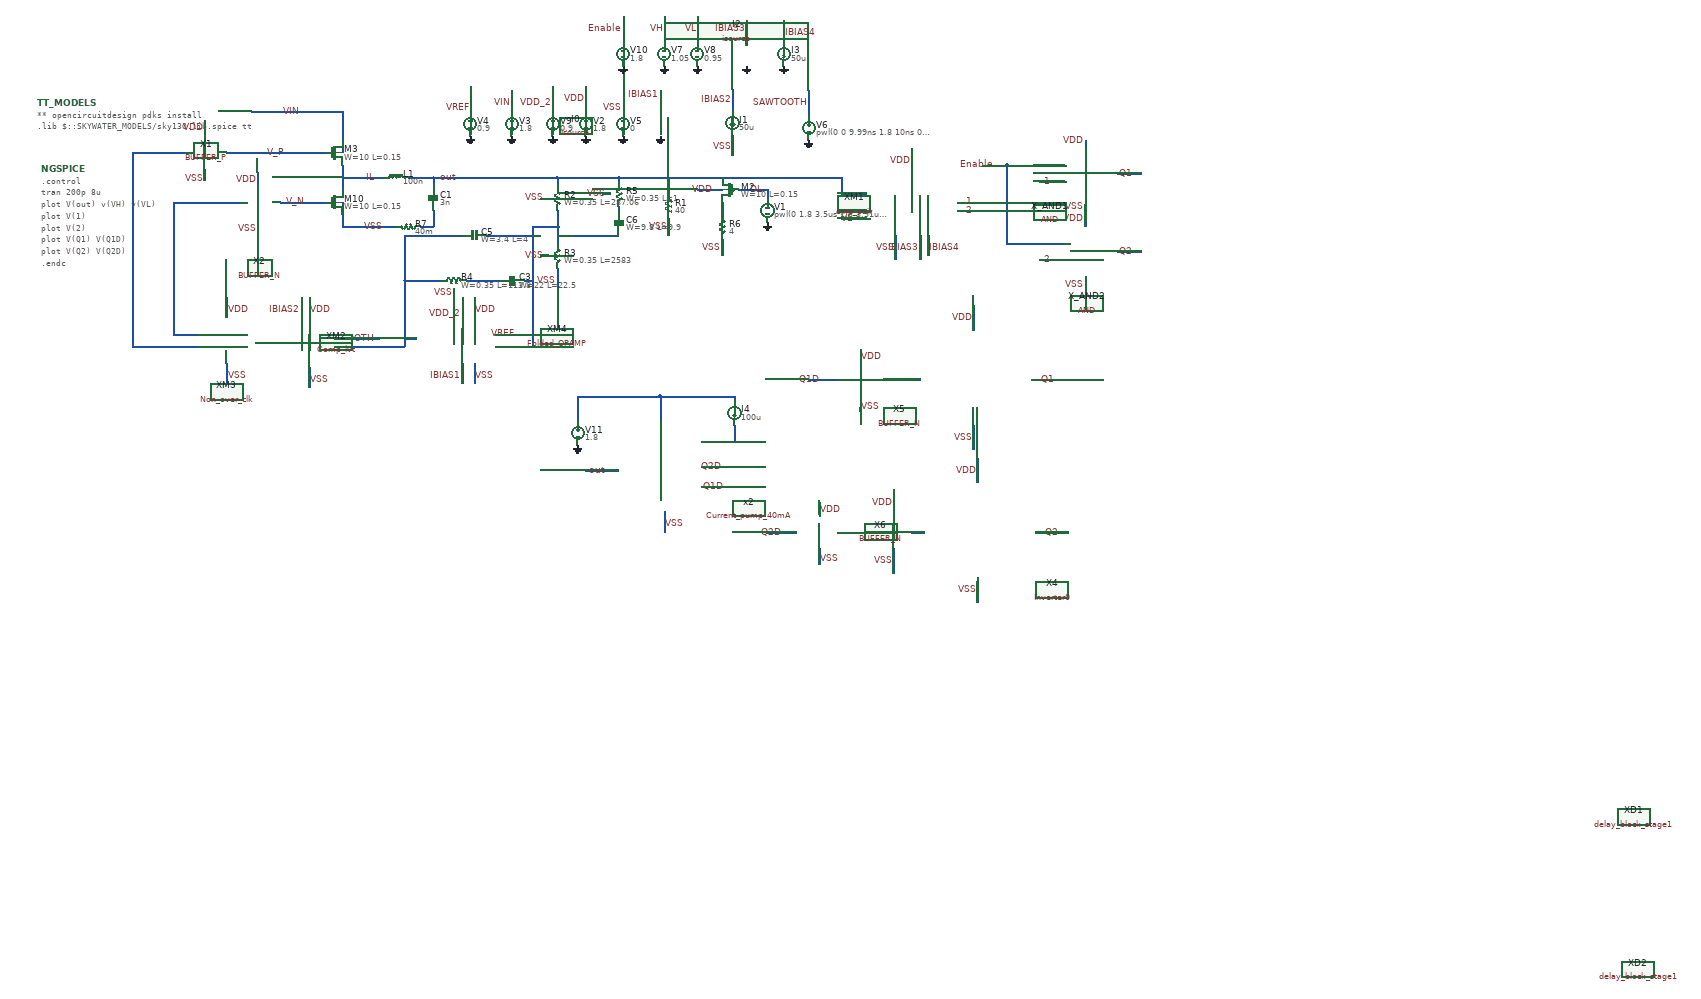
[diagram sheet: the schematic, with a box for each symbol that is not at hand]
v {xschem version=3.0.0 file_version=1.2 }
G {}
K {}
V {}
S {}
E {}
N 470 80 470 140 {
lab=IL}
N 470 20 470 50 {
lab=VIN}
N 380 50 430 50 {
lab=V_P}
N 470 -50 470 20 {
lab=VIN}
N 250 -50 470 -50 {
lab=VIN}
N 470 200 470 230 {
lab=VSS}
N 470 110 530 110 {
lab=IL}
N 530 110 570 110 {
lab=IL}
N 690 110 690 130 {
lab=out}
N 630 110 690 110 {
lab=out}
N 690 190 690 230 {
lab=#net1}
N 690 110 800 110 {
lab=out}
N 790 400 790 450 {
lab=VDD}
N 760 400 760 450 {
lab=VDD_2}
N 790 560 790 610 {
lab=VSS}
N 760 560 760 610 {
lab=IBIAS1}
N 840 520 890 520 {
lab=#net2}
N 840 490 890 490 {
lab=VREF}
N 880 -100 880 -50 {
lab=VIN}
N 980 -110 980 -50 {
lab=VDD_2}
N 1060 -60 1060 -50 {
lab=VDD}
N 1060 -110 1060 -60 {
lab=VDD}
N 1150 -80 1150 -60 {
lab=VSS}
N 1150 -60 1150 -50 {
lab=VSS}
N 1150 -110 1150 -80 {
lab=VSS}
N 1240 -100 1240 -40 {
lab=IBIAS1}
N 390 400 390 450 {
lab=VDD}
N 390 570 390 620 {
lab=VSS}
N 780 -80 780 -60 {
lab=VREF}
N 780 -60 780 -50 {
lab=VREF}
N 780 -110 780 -80 {
lab=VREF}
N 890 520 920 520 {
lab=#net2}
N 1415 7.5 1415 57.5 {
lab=VSS}
N 370 400 370 450 {
lab=IBIAS2}
N 1600 -100 1600 -40 {
lab=SAWTOOTH}
N 190 50 380 50 {
lab=V_P}
N 800 110 980 110 {
lab=out}
N 990 110 990 130 {
lab=out}
N 990 190 990 240 {
lab=#net2}
N 990 330 990 380 {
lab=VSS}
N 770 360 850 360 {
lab=#net3}
N 620 360 710 360 {
lab=#net4}
N 620 360 620 500 {
lab=#net4}
N 930 360 930 490 {
lab=#net2}
N 910 360 930 360 {
lab=#net2}
N 620 250 760 250 {
lab=#net4}
N 820 250 930 250 {
lab=#net2}
N 930 290 930 360 {
lab=#net2}
N 620 500 650 500 {
lab=#net4}
N 930 490 930 520 {
lab=#net2}
N 920 520 930 520 {
lab=#net2}
N 990 110 1140 110 {
lab=out}
N 1140 110 1140 120 {
lab=out}
N 1140 180 1140 190 {
lab=#net5}
N 980 110 990 110 {
lab=out}
N 930 230 930 290 {
lab=#net2}
N 930 230 990 230 {
lab=#net2}
N 990 240 990 270 {
lab=#net2}
N 1260 110 1260 150 {
lab=out}
N 1140 110 1260 110 {
lab=out}
N 1260 210 1260 250 {
lab=VSS}
N 450 520 620 520 {
lab=#net4}
N 620 500 620 520 {
lab=#net4}
N 380 170 430 170 {
lab=V_N}
N 470 170 470 200 {
lab=VSS}
N 1260 110 1390 110 {
lab=out}
N 1390 260 1390 300 {
lab=VSS}
N 1390 170 1390 200 {
lab=#net6}
N 1430 140 1500 140 {
lab=DL}
N 1500 140 1500 160 {
lab=DL}
N 190 400 190 450 {
lab=VDD}
N 190 560 190 610 {
lab=VSS}
N -40 50 90 50 {
lab=#net7}
N -40 50 -40 490 {
lab=#net7}
N 135 90 135 117.5 {
lab=VSS}
N 135 -27.5 135 7.5 {
lab=VDD}
N 320 170 380 170 {
lab=V_N}
N 60 170 220 170 {
lab=#net8}
N 60 170 60 260 {
lab=#net8}
N 265 210 265 247.5 {
lab=VSS}
N 265 97.5 265 127.5 {
lab=VDD}
N 60 490 120 490 {
lab=#net8}
N 60 260 60 490 {
lab=#net8}
N -40 520 120 520 {
lab=#net7}
N -40 490 -40 520 {
lab=#net7}
N 620 250 620 360 {
lab=#net4}
N 990 250 1040 250 {
lab=#net2}
N 1040 250 1140 250 {
lab=#net2}
N 790 560 790 610 {
lab=VSS}
N 1330 140 1390 140 {
lab=VDD}
N 1415 -102.5 1415 -52.5 {
lab=IBIAS2}
N 270 510 320 510 {
lab=#net9}
N 450 500 560 500 {
lab=SAWTOOTH}
N 740 380 740 400 {
lab=VSS}
N 1100 150 1120 150 {
lab=VSS}
N 950 160 970 160 {
lab=VSS}
N 950 300 970 300 {
lab=VSS}
N 470 230 600 230 {
lab=VSS}
N 660 230 690 230 {
lab=#net1}
N 260 510 270 510 {
lab=#net9}
N 1960 170 2010 170 {
lab=1}
N 1960 190 2010 190 {
lab=2}
N 1890 250 1890 300 {
lab=IBIAS4}
N 1870 250 1870 310 {
lab=IBIAS3}
N 1810 250 1810 310 {
lab=VSS}
N 1850 40 1850 100 {
lab=VDD}
N 1680 150 1740 150 {
lab=out}
N 1680 190 1740 190 {
lab=VH}
N 1680 210 1740 210 {
lab=VL}
N 1680 110 1680 150 {
lab=out}
N 1390 110 1680 110 {
lab=out}
N 1450 -270 1450 -210 {
lab=IBIAS3}
N 1540 -270 1540 -220 {
lab=IBIAS4}
N 2080 270 2220 270 {
lab=Enable}
N 2080 80 2220 80 {
lab=Enable}
N 2020 80 2080 80 {
lab=Enable}
N 2160 120 2220 120 {
lab=1}
N 2160 310 2220 310 {
lab=2}
N 2347.5 100 2407.5 100 {
lab=Q1}
N 2347.5 290 2407.5 290 {
lab=Q2}
N 2270 350 2270 370 {
lab=VSS}
N 2270 210 2270 230 {
lab=VDD}
N 2270 160 2270 180 {
lab=VSS}
N 2270 20 2270 40 {
lab=VDD}
N 2080 80 2080 270 {
lab=Enable}
N 1250 -280 1250 -220 {
lab=VH}
N 1330 -280 1330 -220 {
lab=VL}
N 1150 -280 1150 -220 {
lab=Enable}
N 2000 710 2000 770 {
lab=VSS}
N 2000 420 2000 480 {
lab=VDD}
N 2140 600 2220 600 {
lab=Q1}
N 1770 600 1870 600 {
lab=#net10}
N 2010 1080 2010 1140 {
lab=VSS}
N 2010 790 2010 850 {
lab=VDD}
N 2150 970 2230 970 {
lab=Q2}
N 1670 970 1750 970 {
lab=#net11}
N 1805 867.5 1805 927.5 {
lab=VDD}
N 1805 1010 1805 1070 {
lab=VSS}
N 1850 970 1880 970 {
lab=#net12}
N 1600 600 1670 600 {
lab=Q1D}
N 1725 640 1725 677.5 {
lab=VSS}
N 1725 527.5 1725 557.5 {
lab=VDD}
N 1500 970 1570 970 {
lab=Q2D}
N 1625 1010 1625 1047.5 {
lab=VSS}
N 1625 897.5 1625 927.5 {
lab=VDD}
N 1250 920 1250 970 {
lab=VSS}
N 1250 920 1250 970 {
lab=VSS}
N 1040 650 1040 700 {
lab=#net13}
N 1240 640 1240 700 {
lab=#net13}
N 1040 640 1240 640 {
lab=#net13}
N 1040 640 1040 650 {
lab=#net13}
N 1060 820 1140 820 {
lab=out}
N 1340 810 1410 810 {
lab=Q2D}
N 1340 860 1410 860 {
lab=Q1D}
N 1340 750 1420 750 {
lab=#net14}
N 1420 710 1420 750 {
lab=#net14}
N 1240 640 1420 640 {
lab=#net13}
N 1420 640 1420 650 {
lab=#net13}
C {sky130_fd_pr/pfet_01v8.sym} 450 50 0 0 {name=M3
L=0.15
W=10
nf=1
mult=450
ad="'int((nf+1)/2) * W/nf * 0.29'" 
pd="'2*int((nf+1)/2) * (W/nf + 0.29)'"
as="'int((nf+2)/2) * W/nf * 0.29'" 
ps="'2*int((nf+2)/2) * (W/nf + 0.29)'"
nrd="'0.29 / W'" nrs="'0.29 / W'"
sa=0 sb=0 sd=0
model=pfet_01v8
spiceprefix=X
}
C {devices/ind.sym} 600 110 3 0 {name=L1
m=1
value=100n
footprint=1206
device=inductor}
C {devices/capa.sym} 690 160 0 0 {name=C1
m=1
value=3n
footprint=1206
device="ceramic capacitor"}
C {devices/code.sym} -270 -70 0 0 {name=TT_MODELS
only_toplevel=true
format="tcleval( @value )"
value="
** opencircuitdesign pdks install
.lib $::SKYWATER_MODELS/sky130.lib.spice tt

"
spice_ignore=false}
C {devices/code_shown.sym} -260 90 0 0 {name=NGSPICE
only_toplevel=true
value="

.control

tran 200p 8u
plot V(out) v(VH) v(VL)
plot V(1)
plot V(2) 
plot V(Q1) V(Q1D)
plot V(Q2) V(Q2D)
.endc
" }
C {devices/lab_wire.sym} 750 110 0 0 {name=l4 sig_type=std_logic lab=out}
C {devices/lab_wire.sym} 550 110 0 0 {name=l6 sig_type=std_logic lab=IL}
C {devices/lab_wire.sym} 370 -50 0 0 {name=l5 sig_type=std_logic lab=VIN}
C {devices/vsource.sym} 880 -20 0 0 {name=V3 value=1.8}
C {devices/gnd.sym} 880 10 0 0 {name=l7 lab=GND}
C {devices/lab_wire.sym} 880 -70 0 0 {name=l2 sig_type=std_logic lab=VIN}
C {devices/gnd.sym} 1240 10 0 0 {name=l19 lab=GND}
C {devices/lab_wire.sym} 1240 -90 0 0 {name=l22 sig_type=std_logic lab=IBIAS1}
C {devices/isource.sym} 1240 -20 0 0 {name=I0 value=50u}
C {devices/vsource.sym} 980 -20 0 0 {name=V9 value=0.9}
C {devices/gnd.sym} 980 10 0 0 {name=l42 lab=GND}
C {devices/lab_wire.sym} 980 -70 0 0 {name=l8 sig_type=std_logic lab=VDD_2}
C {devices/vsource.sym} 1060 -20 0 0 {name=V2 value=1.8}
C {devices/gnd.sym} 1060 10 0 0 {name=l18 lab=GND}
C {devices/vsource.sym} 1150 -20 0 0 {name=V5 value=0}
C {devices/gnd.sym} 1150 10 0 0 {name=l26 lab=GND}
C {devices/lab_wire.sym} 1150 -60 0 0 {name=l10 sig_type=std_logic lab=VSS}
C {devices/lab_wire.sym} 790 430 0 1 {name=l13 sig_type=std_logic lab=VDD}
C {devices/lab_wire.sym} 760 440 0 0 {name=l14 sig_type=std_logic lab=VDD_2}
C {devices/lab_wire.sym} 570 230 0 0 {name=l1 sig_type=std_logic lab=VSS}
C {devices/lab_wire.sym} 790 590 0 1 {name=l15 sig_type=std_logic lab=VSS}
C {devices/lab_wire.sym} 760 590 0 0 {name=l16 sig_type=std_logic lab=IBIAS1}
C {devices/lab_wire.sym} 390 430 0 1 {name=l11 sig_type=std_logic lab=VDD}
C {devices/lab_wire.sym} 390 600 0 1 {name=l12 sig_type=std_logic lab=VSS}
C {devices/vsource.sym} 780 -20 0 0 {name=V4 value=0.9}
C {devices/gnd.sym} 780 10 0 0 {name=l17 lab=GND}
C {devices/lab_wire.sym} 780 -60 0 0 {name=l20 sig_type=std_logic lab=VREF}
C {devices/isource.sym} 1415 -22.5 0 1 {name=I1 value=50u}
C {devices/lab_wire.sym} 370 430 0 0 {name=l27 sig_type=std_logic lab=IBIAS2}
C {devices/vsource.sym} 1600 -10 0 0 {name=V6 value="pwl(0 0 9.99ns 1.8 10ns 0) r=0"}
C {devices/gnd.sym} 1600 20 0 0 {name=l28 lab=GND}
C {devices/gnd.sym} 1600 20 0 0 {name=l29 lab=GND}
C {devices/lab_wire.sym} 1600 -70 0 0 {name=l30 sig_type=std_logic lab=SAWTOOTH}
C {devices/lab_wire.sym} 990 360 0 0 {name=l31 sig_type=std_logic lab=VSS}
C {devices/lab_wire.sym} 890 490 0 0 {name=l33 sig_type=std_logic lab=VREF}
C {devices/lab_wire.sym} 550 500 0 0 {name=l32 sig_type=std_logic lab=SAWTOOTH}
C {devices/lab_wire.sym} 1260 230 0 0 {name=l21 sig_type=std_logic lab=VSS}
C {sky130_fd_pr/pfet_01v8.sym} 1410 140 0 1 {name=M2
L=0.15
W=10
nf=1
mult=450
ad="'int((nf+1)/2) * W/nf * 0.29'" 
pd="'2*int((nf+1)/2) * (W/nf + 0.29)'"
as="'int((nf+2)/2) * W/nf * 0.29'" 
ps="'2*int((nf+2)/2) * (W/nf + 0.29)'"
nrd="'0.29 / W'" nrs="'0.29 / W'"
sa=0 sb=0 sd=0
model=pfet_01v8
spiceprefix=X
}
C {devices/lab_wire.sym} 1390 280 0 0 {name=l23 sig_type=std_logic lab=VSS}
C {devices/vsource.sym} 1500 190 0 0 {name=V1 value="pwl(0 1.8 3.5us 1.8 3.51us 0 7us 0) r=0"}
C {devices/gnd.sym} 1500 220 0 0 {name=l34 lab=GND}
C {devices/gnd.sym} 1500 220 0 0 {name=l36 lab=GND}
C {devices/lab_wire.sym} 190 430 0 1 {name=l35 sig_type=std_logic lab=VDD}
C {devices/lab_wire.sym} 190 590 0 1 {name=l37 sig_type=std_logic lab=VSS}
C {DC_DC_Converter/BUFFER/BUFFER_PMOS/BUFFER_P.sym} 70 100 0 0 {name=X1}
C {devices/lab_wire.sym} 135 -10 0 0 {name=l38 sig_type=std_logic lab=VDD}
C {devices/lab_wire.sym} 135 112.5 0 0 {name=l40 sig_type=std_logic lab=VSS}
C {DC_DC_Converter/BUFFER/BUFFER_NMOS/BUFFER_N.sym} 130 250 0 0 {name=X2}
C {devices/lab_wire.sym} 265 235 0 0 {name=l39 sig_type=std_logic lab=VSS}
C {devices/lab_wire.sym} 265 115 0 0 {name=l41 sig_type=std_logic lab=VDD}
C {DC_DC_Converter/Non_Overlap_Clk/Non_over_clk.sym} 390 770 0 1 {name=XM3}
C {devices/lab_wire.sym} 330 50 0 0 {name=l3 sig_type=std_logic lab=V_P}
C {devices/lab_wire.sym} 380 170 0 0 {name=l43 sig_type=std_logic lab=V_N}
C {DC_DC_Converter/Folded_OPAMP/Folded_OPAMP.sym} 850 560 0 1 {name=XM4}
C {devices/lab_wire.sym} 1490 140 0 0 {name=l96 sig_type=std_logic lab=DL}
C {sky130_fd_pr/cap_mim_m3_1.sym} 790 250 3 0 {name=C5 model=cap_mim_m3_1 W=3.4 L=4 MF=1 spiceprefix=X}
C {sky130_fd_pr/cap_mim_m3_1.sym} 880 360 3 0 {name=C3 model=cap_mim_m3_1 W=22 L=22.5 MF=1 spiceprefix=X}
C {sky130_fd_pr/cap_mim_m3_1.sym} 1140 220 0 0 {name=C6 model=cap_mim_m3_1 W=9.8 L=9.9 MF=1 spiceprefix=X}
C {devices/lab_wire.sym} 1060 -80 0 0 {name=l97 sig_type=std_logic lab=VDD}
C {devices/lab_wire.sym} 1370 140 0 0 {name=l98 sig_type=std_logic lab=VDD}
C {sky130_fd_pr/nfet_01v8.sym} 450 170 0 0 {name=M10
L=0.15
W=10
nf=1 
mult=150
ad="'int((nf+1)/2) * W/nf * 0.29'" 
pd="'2*int((nf+1)/2) * (W/nf + 0.29)'"
as="'int((nf+2)/2) * W/nf * 0.29'" 
ps="'2*int((nf+2)/2) * (W/nf + 0.29)'"
nrd="'0.29 / W'" nrs="'0.29 / W'"
sa=0 sb=0 sd=0
model=nfet_01v8
spiceprefix=X
}
C {devices/lab_wire.sym} 1415 -77.5 0 0 {name=l24 sig_type=std_logic lab=IBIAS2}
C {devices/lab_wire.sym} 1415 35 0 0 {name=l25 sig_type=std_logic lab=VSS}
C {sky130_fd_pr/res_high_po_0p35.sym} 740 360 3 0 {name=R4
W=0.35
L=113.8
model=res_high_po_0p35
spiceprefix=X
mult=1}
C {devices/lab_wire.sym} 740 390 3 0 {name=l9 sig_type=std_logic lab=VSS}
C {sky130_fd_pr/res_high_po_0p35.sym} 1140 150 0 0 {name=R5
W=0.35
L=1
model=res_high_po_0p35
spiceprefix=X
mult=1}
C {devices/lab_wire.sym} 1110 150 0 0 {name=l44 sig_type=std_logic lab=VSS}
C {sky130_fd_pr/res_high_po_0p35.sym} 990 160 0 0 {name=R2
W=0.35
L=287.06
model=res_high_po_0p35
spiceprefix=X
mult=1}
C {devices/lab_wire.sym} 960 160 0 0 {name=l45 sig_type=std_logic lab=VSS}
C {sky130_fd_pr/res_high_po_0p35.sym} 990 300 0 0 {name=R3
W=0.35
L=2583
model=res_high_po_0p35
spiceprefix=X
mult=1}
C {devices/lab_wire.sym} 960 300 0 0 {name=l46 sig_type=std_logic lab=VSS}
C {devices/res.sym} 630 230 1 0 {name=R7
value=40m
footprint=1206
device=resistor
m=1}
C {devices/res.sym} 1260 180 0 0 {name=R1
value=40
footprint=1206
device=resistor
m=1}
C {devices/res.sym} 1390 230 0 0 {name=R6
value=4
footprint=1206
device=resistor
m=1}
C {DC_DC_Converter/Comparator/Comp_lvt.sym} 470 580 0 1 {name=XM2}
C {devices/lab_wire.sym} 1890 280 0 1 {name=l48 sig_type=std_logic lab=IBIAS4}
C {devices/lab_wire.sym} 1870 280 0 0 {name=l49 sig_type=std_logic lab=IBIAS3}
C {devices/lab_pin.sym} 1810 280 0 0 {name=l50 sig_type=std_logic lab=VSS}
C {devices/lab_pin.sym} 1850 70 0 0 {name=l51 sig_type=std_logic lab=VDD}
C {devices/lab_pin.sym} 1710 190 1 0 {name=l53 sig_type=std_logic lab=VH}
C {devices/lab_pin.sym} 1710 210 3 0 {name=l54 sig_type=std_logic lab=VL}
C {DC_DC_Converter/Comparator_Pair/cmp_pair.sym} 1720 250 0 0 {name=XM1}
C {devices/lab_wire.sym} 2000 170 0 0 {name=l47 sig_type=std_logic lab=1}
C {devices/lab_wire.sym} 2000 190 0 0 {name=l87 sig_type=std_logic lab=2}
C {devices/gnd.sym} 1450 -160 0 0 {name=l58 lab=GND}
C {devices/isource.sym} 1450 -190 0 0 {name=I2 value=50u}
C {devices/isource.sym} 1540 -190 0 0 {name=I3 value=50u}
C {devices/gnd.sym} 1540 -160 0 0 {name=l60 lab=GND}
C {devices/lab_wire.sym} 1450 -250 0 0 {name=l59 sig_type=std_logic lab=IBIAS3}
C {devices/lab_wire.sym} 1540 -240 0 1 {name=l61 sig_type=std_logic lab=IBIAS4}
C {devices/lab_pin.sym} 2270 370 0 0 {name=l84 sig_type=std_logic lab=VSS}
C {devices/lab_wire.sym} 2387.5 290 0 0 {name=l86 sig_type=std_logic lab=Q2}
C {devices/lab_wire.sym} 2190 120 0 0 {name=l64 sig_type=std_logic lab=1}
C {devices/lab_wire.sym} 2190 310 0 0 {name=l88 sig_type=std_logic lab=2}
C {devices/lab_wire.sym} 2050 80 0 0 {name=l91 sig_type=std_logic lab=Enable}
C {devices/lab_pin.sym} 2270 210 0 0 {name=l94 sig_type=std_logic lab=VDD}
C {devices/lab_wire.sym} 2387.5 100 0 0 {name=l79 sig_type=std_logic lab=Q1}
C {devices/lab_pin.sym} 2270 180 0 0 {name=l52 sig_type=std_logic lab=VSS}
C {devices/lab_pin.sym} 2270 20 0 0 {name=l55 sig_type=std_logic lab=VDD}
C {devices/vsource.sym} 1250 -190 0 0 {name=V7 value=1.05}
C {devices/gnd.sym} 1250 -160 0 0 {name=l56 lab=GND}
C {devices/lab_pin.sym} 1250 -250 0 0 {name=l57 sig_type=std_logic lab=VH}
C {devices/vsource.sym} 1330 -190 0 0 {name=V8 value=0.95}
C {devices/gnd.sym} 1330 -160 0 0 {name=l65 lab=GND}
C {devices/lab_pin.sym} 1330 -250 0 0 {name=l66 sig_type=std_logic lab=VL}
C {devices/gnd.sym} 1150 -160 0 0 {name=l89 lab=GND}
C {devices/lab_pin.sym} 1150 -250 0 0 {name=l90 sig_type=std_logic lab=Enable}
C {devices/vsource.sym} 1150 -190 0 0 {name=V10 value=1.8}
C {DC_DC_Converter/Delay_block_revised/AND_GATE/AND.sym} 2200 170 0 0 {name=X_AND1}
C {DC_DC_Converter/Delay_block_revised/AND_GATE/AND.sym} 2200 360 0 0 {name=X_AND2}
C {devices/lab_pin.sym} 2000 740 0 0 {name=l67 sig_type=std_logic lab=VSS}
C {devices/lab_pin.sym} 2000 450 0 0 {name=l68 sig_type=std_logic lab=VDD}
C {devices/lab_wire.sym} 2197.5 600 0 0 {name=l69 sig_type=std_logic lab=Q1}
C {devices/lab_pin.sym} 2010 1110 0 0 {name=l70 sig_type=std_logic lab=VSS}
C {devices/lab_pin.sym} 2010 820 0 0 {name=l71 sig_type=std_logic lab=VDD}
C {devices/lab_wire.sym} 1537.5 970 0 0 {name=l72 sig_type=std_logic lab=Q2D}
C {devices/lab_wire.sym} 2207.5 970 0 0 {name=l73 sig_type=std_logic lab=Q2}
C {DC_DC_Converter/Delay_block_revised/delay_block_stage1.sym} 3600 1660 0 1 {name=XD1}
C {DC_DC_Converter/Delay_block_revised/delay_block_stage1.sym} 3610 2030 0 1 {name=XD2}
C {devices/lab_wire.sym} 1397.5 860 0 0 {name=l77 sig_type=std_logic lab=Q1D}
C {DC_DC_Converter/Delay_block_revised/Inverter_0/Inverter0.sym} 2070 1090 0 1 {name=X4}
C {devices/lab_pin.sym} 1805 897.5 0 0 {name=l63 sig_type=std_logic lab=VDD}
C {devices/lab_pin.sym} 1805 1040 0 0 {name=l75 sig_type=std_logic lab=VSS}
C {devices/lab_wire.sym} 1630 600 1 0 {name=l78 sig_type=std_logic lab=Q1D}
C {devices/lab_wire.sym} 1392.5 810 0 0 {name=l74 sig_type=std_logic lab=Q2D}
C {DC_DC_Converter/BUFFER/BUFFER_NMOS/BUFFER_N.sym} 1860 680 0 1 {name=X5}
C {devices/lab_wire.sym} 1725 665 0 1 {name=l81 sig_type=std_logic lab=VSS}
C {devices/lab_wire.sym} 1725 545 0 1 {name=l83 sig_type=std_logic lab=VDD}
C {DC_DC_Converter/BUFFER/BUFFER_NMOS/BUFFER_N.sym} 1760 1050 0 1 {name=X6}
C {devices/lab_wire.sym} 1625 1035 0 1 {name=l85 sig_type=std_logic lab=VSS}
C {devices/lab_wire.sym} 1625 915 0 1 {name=l92 sig_type=std_logic lab=VDD}
C {devices/lab_wire.sym} 1250 950 0 1 {name=l80 sig_type=std_logic lab=VSS}
C {devices/vsource.sym} 1040 730 0 0 {name=V11 value=1.8}
C {devices/gnd.sym} 1040 760 0 0 {name=l104 lab=GND}
C {DC_DC_Converter/Current_pump_mirror/Current_pump_40mA.sym} 1580 800 0 1 {name=x2}
C {devices/isource.sym} 1420 680 0 0 {name=I4 value=100u}
C {devices/lab_wire.sym} 1110 820 0 0 {name=l82 sig_type=std_logic lab=out}
